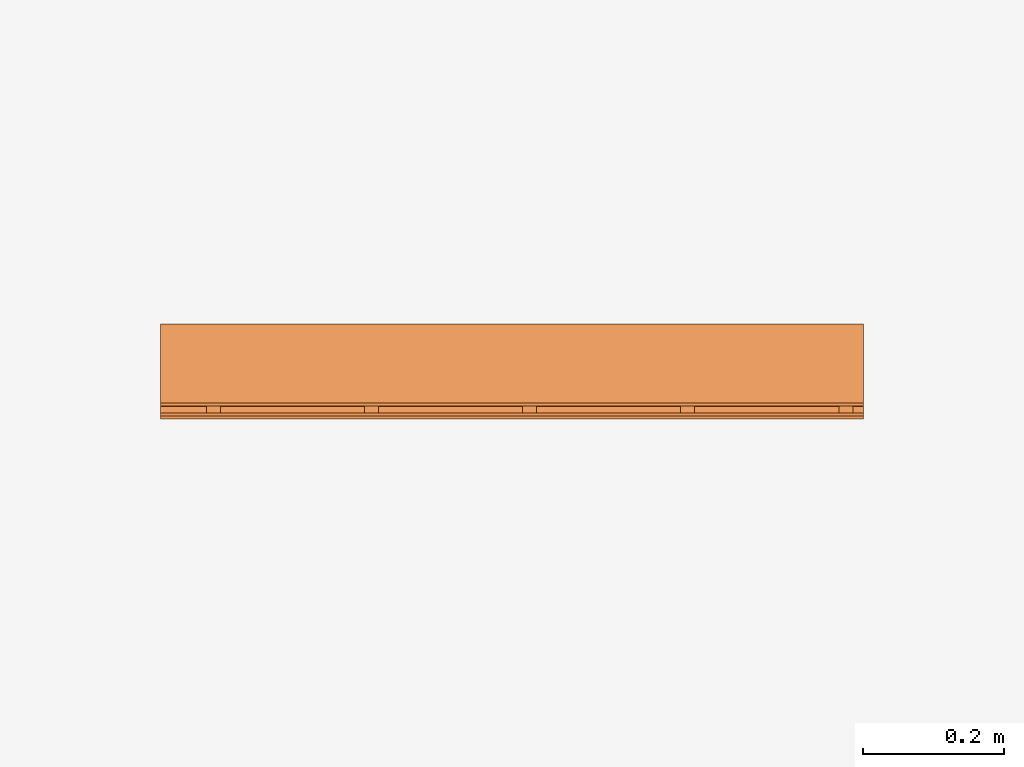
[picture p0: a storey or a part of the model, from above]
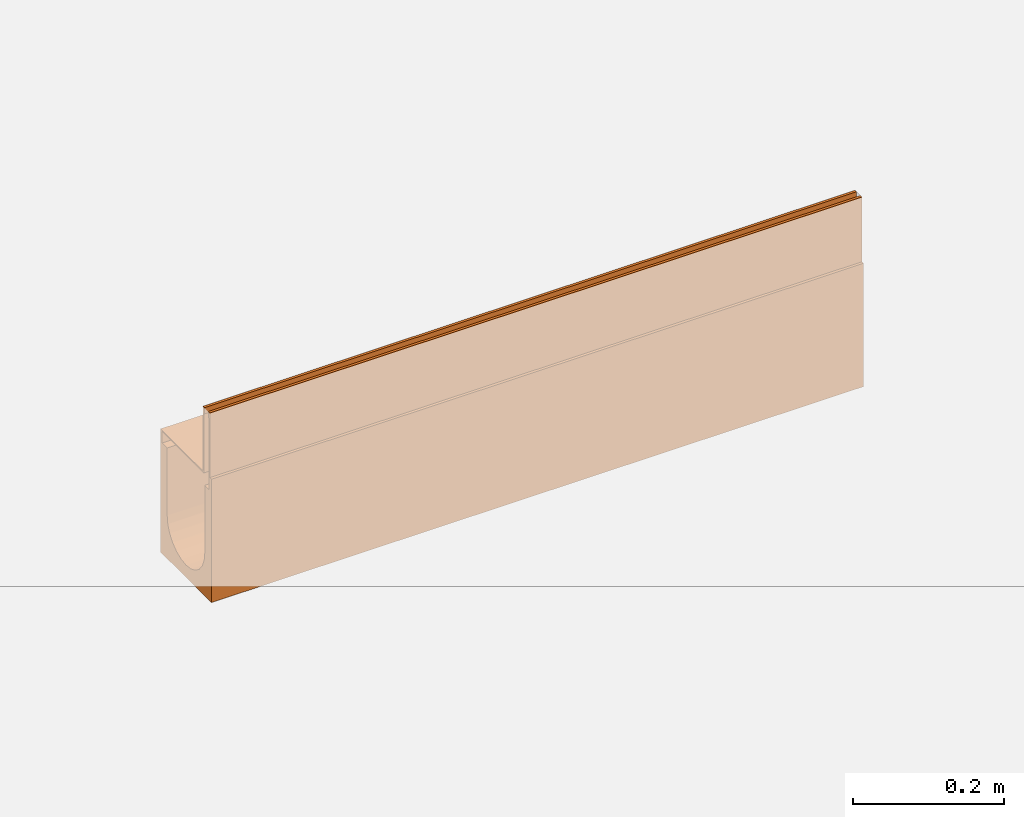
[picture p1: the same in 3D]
Properties of the parts of a building model (IFC2X3)

# File
Description: ViewDefinition [CoordinationView]
File name: 23100 - No 10.0 Constant Depth Channel - 1000mm LG - Invert Depth 180mm.ifc
Time: 2013-10-31T17:31:49
Written by: Autodesk Revit 2013
Made in: 20120221_2030(x64)

# IfcProject, Project Number
LongName: Project Name; Phase: Project Status

# IfcSite, Default
RefLatitude: 42, 21, 30, 344238; RefLongitude: -71, -3, -35, -194702; RefElevation: 0 mm

# IfcBuilding
Pset_BuildingCommon - NumberOfStoreys: 1
Other - Project Name: Project Name; Project Number: Project Number; Project Issue Date: Issue Date; Project Address: ## Street City, State Zip; Client Name: Owner; Project Status: Project Status

# IfcBuildingStorey, Level 1
LongName: Level 1; Elevation: 0 mm
Constraints - Elevation Base: 0; Elevation: 0 mm
Graphics - Symbol: M_Level Head - Circle: M_Level Head - Circle; Symbol at End 2 Default: yes; Line Weight: 1; Symbol at End 1 Default: no; Color: 0; Line Pattern: Center
Identity Data - Building Story: yes; Name: Level 1; Structural: no
Dimensions - Computation Height: 0 mm

# IfcBuildingElementProxy: 23100 - No 10.0 Constant Depth Channel - 1000mm LG - Invert Depth 180mm, Civil-Drainage-Channel-ACO-MultiDrain-M100D-Brickslot-Channel-System:23100 - No 10.0 Constant Depth Channel - 1000mm LG - Invert Depth 180mm:23100 - No 10.0 Constant Depth Channel - 1000mm LG - Invert Depth 180mm:196059
In: Level 1
Material: Steel, Galvanized, Vienite® Synthetic Resin Concrete
Dimensions - EndCap Position: 1000 mm; Volume: 10242822 mm3; Custom_Void_length: 0 mm; Length: 1000 mm; Brickslot Access Unit Void Bottom Depth: -6605 mm; FloorCut_Length: -1000 mm; Brickslot Void Length: 1000 mm; Brickslot Access Unit Void Depth: -6500 mm; Brickslot Void Depth: 0 mm; Depth: 200 mm; Brickslot Access Unit Floor Cut Length: 500 mm; ShallowOverallDepth: 75 mm; SlopingInvertDepth: 175 mm; SlopingOverallDepth: 245 mm; Length Drain: -1000 mm; Floor Cut Gap: 105 mm; SlopingEndInvertDepth: 180 mm; ShallowInvDepth: 55 mm; InvDepth: 130 mm; SlopingEndOverallDepth: 250 mm; FloorCut_Width: 135 mm; GratingLength: -1000 mm; EndCap_Height: 200 mm; FloorCut_Depth: 200 mm; Access_Custom_Void_Length: 0 mm
Construction - 23404_Universal Endcap (Male End): no; 23467_Load Class D400_Brickslot Access Unit_Galvanised Steel_500mm Long: no; 23461_Load Class C250_Brickslot Grating_Galvanized Steel_500mm Long: no; 23465_Load Class D400_Brickslot Grating_Galvanized Steel_1000mm Long: yes; 23462_Load Class C250_Brickslot Access Unit_Galvanised Steel_500mm Long: no; 23404_Universal Endcap (Female End): no; 23466_Load Class D400_Brickslot Grating_Galvanized Steel_500mm Long: no; 23460_Load Class C250_Brickslot Grating_Galvanized Steel_1000mm Long: no; Constant Depth Channel: yes; Shallow Depth Channel with seal: no; Sloping Channel: no; 23410_Sump Unit: no; Constant Depth Junction Channel: no; Shallow Depth Channel: no
Phasing - Phase Created: New Construction
Constraints - Moves With Nearby Elements: no; Level: Level: Level 1
Pset_BuildingElementProxyCommon - Reference: 23100 - No 10.0 Constant Depth Channel - 1000mm LG - Invert Depth 180mm
Materials and Finishes - Edge Rail Finish: Pre-galvanised; Edge Rail Colour: Silver; Channel Material: Vienite® Synthetic Resin Concrete; Edge Rail Material: Steel; Channel Colour: Brown
Data - Product Weight: 16.2 Kg; Invert Depth: 180mm; Product Standard: BS EN 1433:2002, CE marked; Concrete Surround Volume - Load Class B 125 - C 250 - Concrete Pavement: 0.13m³/m; Concrete Surround Volume - Load Class A 15 - Concrete Pavement: 0.08m³/m; Concrete Surround Volume - Load Class D 400 - Concrete Pavement: 0.19m³/m; ACO Hydraulic Design Software: http://www.acodesign.co.uk; Product Dimensions: 1000mm x 135mm x 200mm (LxWxH); Installation - Concrete Grade: Refer to brochure; Load Class: A 15 - D 400; Hydraulic Performance: http://www.aco.co.uk/download.php?id=173; Pre-formed Outlet Ø: N/A; Channel C.S.A: 0.013m²
Identity Data - Fax: +44 (0)1462 815895; e-mail Technical: technical@aco.co.uk; Model: ACO MultiDrain MD Brickslot- M100D; Type Comments: ACO MultiDrain M100D 10.0 Constant Depth Channel 1000mm Long; Watermarked With: BIM Manager Premium Suite; Address: ACO Business Park, Hitchin Road, Shefford, Bedfordshire, United Kingdom SG17 5TE; Manufacturer: ACO Technologies plc - ACO Water Management Division; Installation guidelines: http://www.aco.co.uk/download.php?id=173; Product brochure: http://www.aco.co.uk/download.php?id=173; OmniClass Title: Rainwater Removal; OmniClass Number: 23.70.50.24; Model Description: Channel drainage system; Cost: 0; Maintenance guidelines: http://www.aco.co.uk/download.php?id=173; Price: POA - contact ACO; Assembly Code: D2040; Telephone: +44 (0)1462 816666; e-mail Sales: customersupport@aco.co.uk; Assembly Description: Rain Water Drainage; Watermark 1: This file is the property of ACO Technologies PLC; Product Code: 23100; Product Page URL: http://www.aco.co.uk/product_detail.php?id=58; URL: www.aco.co.uk; Watermark 2: This file is water marked and users are prohibited to reproduce, adapt, distribute this information
General - TagNumber: 0; SerialNumber: 0
Green Building Properties - Edge Rail Recyclable: Fully recyclable; Edge Rail Recycled Material Content: Between 40% - 90%; Channel Recycled Material Content: 20% minimum; Channel Recyclable: Fully recyclable
Other - Revision: 1; Created By: www.aco.co.uk; Watermarked By: www.aco.co.uk
Model Properties - Brickslot Grating Product code 23461: Load Class C250 - Brickslot Galvanised Steel - 500mm long x 105mm high - 10mm Slot - Intake area - 10000mm²/m -3.3 Kg; Brickslot Access Unit Product code 23462: Load Class C250 - Brickslot Access Unit Galvanised Steel - 500mm long x 105mm high - 10mm Slot - Intake area - 10000mm²/m - 6.4 Kg; Brickslot Access Unit Product code 23467: Load Class D400 - Brickslot Access Unit Galvanised Steel - 500mm long x 105mm high - 10mm Slot - Intake area - 10000mm²/m - 6.4 Kg; End Cap Product code 23404: No 306 Universal End Cap - 135mm wide x 300mm long - Spigot Ø110mm x 50mm long - Silver - Polypropylene - 0.16kg; Brickslot Grating Product code 23466: Load Class D400 - Brickslot Galvanised Steel - 500mm long x 105mm high - 10mm Slot - Intake area - 10000mm²/m - 3.3 Kg; Brickslot Grating Product code 23465: Load Class D400 - Brickslot Galvanised Steel - 1000mm long x 105mm high - 10mm Slot - Intake area - 10000mm²/m - 6.6 Kg; Brickslot Grating Product code 23460: Load Class C250 - Brickslot Galvanised Steel - 1000mm long x 105mm high - 10mm Slot - Intake area - 10000mm²/m - 6.6 Kg

# IfcOpeningElement: Recess (2)
In: Level 1
Dimensions - Area: 25000000 mm2; Perimeter: 20000 mm; Volume: 24971110000 mm3; Thickness: 1000 mm
Constraints - Room Bounding: yes; Level: Level: Level 1; Height Offset From Level: 0 mm; Related to Mass: no
Phasing - Phase Created: New Construction
Structural - Enable Analytical Model: no; Structural: no
Analytical Properties - Heat Transfer Coefficient (U): 0.837; Roughness: 1; Absorptance: 0.1; Thermal mass: 1359800; Thermal Resistance (R): 1.19474
Graphics - Coarse Scale Fill Color: 0
Construction - Function: 0; Default Thickness: 1000 mm
Materials and Finishes - Structural Material: Earth

# IfcSlab: Floor:Generic Floor - 1000mm, Floor:Generic Floor - 1000mm:193825
In: Level 1
PredefinedType: FLOOR; Material: Earth 1000 mm
Dimensions - Area: 25000000 mm2; Perimeter: 20000 mm; Volume: 24971110000 mm3; Thickness: 1000 mm
Constraints - Room Bounding: yes; Level: Level: Level 1; Height Offset From Level: 0 mm; Related to Mass: no
Phasing - Phase Created: New Construction
Structural - Enable Analytical Model: no; Structural: no
Pset_SlabCommon - Reference: Generic Floor - 1000mm; IsExternal: no; LoadBearing: yes
Analytical Properties - Heat Transfer Coefficient (U): 0.837; Roughness: 1; Absorptance: 0.1; Thermal mass: 1359800; Thermal Resistance (R): 1.19474
Graphics - Coarse Scale Fill Color: 0
Construction - Function: 0; Default Thickness: 1000 mm
Materials and Finishes - Structural Material: Earth
